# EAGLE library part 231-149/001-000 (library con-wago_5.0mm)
Serie 231, Stiftleiste mit geraden Einlötstiften / Series 231, Male connector with straight solder pins Polzahl / Pole No.: 19 Rastermaß / Pitch: 5 mm Bemessungsspannung / Rated Voltage: 320 V Nennstrom / Nominal Current: 12 A Lötstiftlänge: / Solder Pin Length: 5 mm Farbe / Color: grau / gray Stand: 01.01.2012. Die jeweils aktuellen Daten zu diesem Artikel finden Sie in unserem Produktkatalog, den Sie unter www.wago.com einsehen können. As of: 01/01/2012. Please find the newest data for this article in our product catalogue, which can be viewed under www.wago.com.

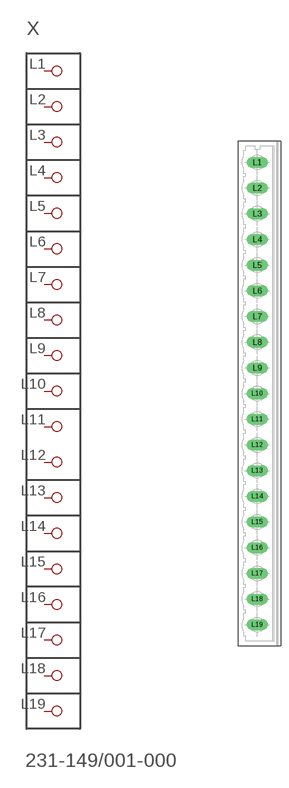
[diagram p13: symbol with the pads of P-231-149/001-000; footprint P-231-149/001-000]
Designator prefix X

## 231-149/001-000  [P-231-149/001-000]
L1  P1
L2  P2
L3  P3
L4  P4
L5  P5
L6  P6
L7  P7
L8  P8
L9  P9
L10  P10
L11  P11
L12  P12
L13  P13
L14  P14
L15  P15
L16  P16
L17  P17
L18  P18
L19  P19

## Footprint P-231-149/001-000 (pad centres in mm)
drill 1.4 long: L1 -0.4,45; L2 -0.4,40; L3 -0.4,35; L4 -0.4,30; L5 -0.4,25; L6 -0.4,20; L7 -0.4,15; L8 -0.4,10; L9 -0.4,5; L10 -0.4,0; L11 -0.4,-5; L12 -0.4,-10; L13 -0.4,-15; L14 -0.4,-20; L15 -0.4,-25; L16 -0.4,-30; L17 -0.4,-35; L18 -0.4,-40; L19 -0.4,-45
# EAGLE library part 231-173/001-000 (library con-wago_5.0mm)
Serie 231, Stiftleiste mit geraden Einlötstiften / Series 231, Male connector with straight solder pins Polzahl / Pole No.: 13 Rastermaß / Pitch: 5 mm Bemessungsspannung / Rated Voltage: 320 V Nennstrom / Nominal Current: 12 A Lötstiftlänge: / Solder Pin Length: 5 mm Farbe / Color: grau / gray Stand: 01.01.2012. Die jeweils aktuellen Daten zu diesem Artikel finden Sie in unserem Produktkatalog, den Sie unter www.wago.com einsehen können. As of: 01/01/2012. Please find the newest data for this article in our product catalogue, which can be viewed under www.wago.com.

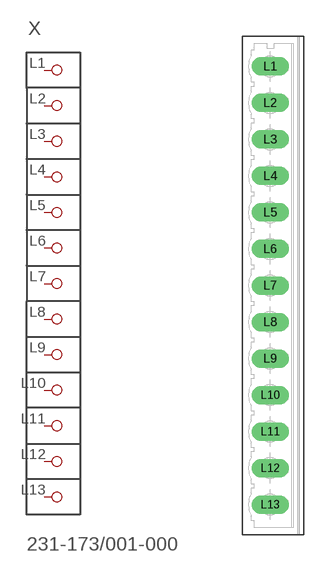
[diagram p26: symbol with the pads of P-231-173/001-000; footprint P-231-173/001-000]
Designator prefix X

## 231-173/001-000  [P-231-173/001-000]
L1  P1
L2  P2
L3  P3
L4  P4
L5  P5
L6  P6
L7  P7
L8  P8
L9  P9
L10  P10
L11  P11
L12  P12
L13  P13

## Footprint P-231-173/001-000 (pad centres in mm)
drill 1.7 long: L1 -0.4,30; L2 -0.4,25; L3 -0.4,20; L4 -0.4,15; L5 -0.4,10; L6 -0.4,5; L7 -0.4,0; L8 -0.4,-5; L9 -0.4,-10; L10 -0.4,-15; L11 -0.4,-20; L12 -0.4,-25; L13 -0.4,-30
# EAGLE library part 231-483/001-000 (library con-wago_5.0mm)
Serie 231, Stiftleiste mit abgewinkelten Einlötstiften / Series 231, Male connector with angled solder pins Polzahl / Pole No.: 23 Rastermaß / Pitch: 5 mm Bemessungsspannung / Rated Voltage: 320 V Nennstrom / Nominal Current: 16 A Lötstiftlänge: / Solder Pin Length: 3.8 mm Farbe / Color: grau / gray Stand: 01.01.2012. Die jeweils aktuellen Daten zu diesem Artikel finden Sie in unserem Produktkatalog, den Sie unter www.wago.com einsehen können. As of: 01/01/2012. Please find the newest data for this article in our product catalogue, which can be viewed under www.wago.com.

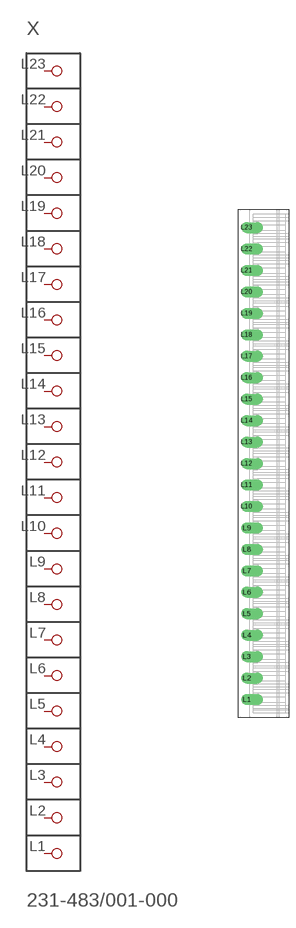
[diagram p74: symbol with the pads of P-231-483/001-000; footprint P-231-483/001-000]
Designator prefix X

## 231-483/001-000  [P-231-483/001-000]
L1  P1
L2  P2
L3  P3
L4  P4
L5  P5
L6  P6
L7  P7
L8  P8
L9  P9
L10  P10
L11  P11
L12  P12
L13  P13
L14  P14
L15  P15
L16  P16
L17  P17
L18  P18
L19  P19
L20  P20
L21  P21
L22  P22
L23  P23

## Footprint P-231-483/001-000 (pad centres in mm)
drill 1.7 offset: L1 -4,-55; L2 -4,-50; L3 -4,-45; L4 -4,-40; L5 -4,-35; L6 -4,-30; L7 -4,-25; L8 -4,-20; L9 -4,-15; L10 -4,-10; L11 -4,-5; L12 -4,0; L13 -4,5; L14 -4,10; L15 -4,15; L16 -4,20; L17 -4,25; L18 -4,30; L19 -4,35; L20 -4,40; L21 -4,45; L22 -4,50; L23 -4,55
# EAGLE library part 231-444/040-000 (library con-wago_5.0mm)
Serie 231, Stiftleiste (für Leiterplatten) Einlötstift abgewinkelt 1 x 1 mm / Series 231, Male header (for PCBs) Angled solder pin 1 x 1 mm Polzahl / Pole No.: 14 Rastermaß / Pitch: 5 mm Bemessungsspannung / Rated Voltage: 320 V Nennstrom / Nominal Current: 12 A Lötstiftlänge: / Solder Pin Length: 5 mm Farbe / Color: grau / gray Stand: 01.01.2012. Die jeweils aktuellen Daten zu diesem Artikel finden Sie in unserem Produktkatalog, den Sie unter www.wago.com einsehen können. As of: 01/01/2012. Please find the newest data for this article in our product catalogue, which can be viewed under www.wago.com.

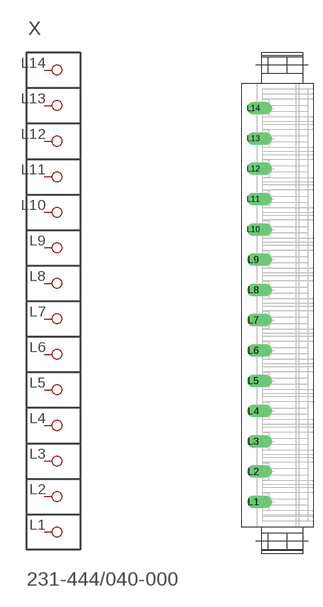
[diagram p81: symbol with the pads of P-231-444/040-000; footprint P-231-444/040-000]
Designator prefix X

## 231-444/040-000  [P-231-444/040-000]
L1  P1
L2  P2
L3  P3
L4  P4
L5  P5
L6  P6
L7  P7
L8  P8
L9  P9
L10  P10
L11  P11
L12  P12
L13  P13
L14  P14

## Footprint P-231-444/040-000 (pad centres in mm)
drill 1.4 offset: L1 -4,-32.8; L2 -4,-27.8; L3 -4,-22.8; L4 -4,-17.8; L5 -4,-12.8; L6 -4,-7.8; L7 -4,-2.8; L8 -4,2.2; L9 -4,7.2; L10 -4,12.2; L11 -4,17.2; L12 -4,22.2; L13 -4,27.2; L14 -4,32.2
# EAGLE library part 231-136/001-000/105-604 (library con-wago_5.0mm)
Serie 231, Stiftleiste mit geraden Einlötstiften / Series 231, Male connector with straight solder pins Polzahl / Pole No.: 6 Rastermaß / Pitch: 5 mm Bemessungsspannung / Rated Voltage: 320 V Nennstrom / Nominal Current: 12 A Lötstiftlänge: / Solder Pin Length: 2.4 mm Farbe / Color: schwarz / black Stand: 01.01.2012. Die jeweils aktuellen Daten zu diesem Artikel finden Sie in unserem Produktkatalog, den Sie unter www.wago.com einsehen können. As of: 01/01/2012. Please find the newest data for this article in our product catalogue, which can be viewed under www.wago.com.

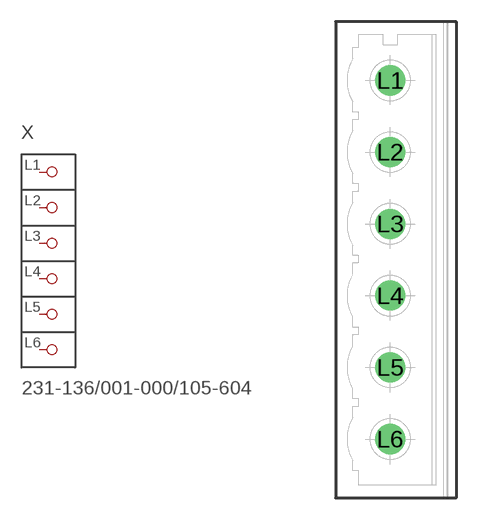
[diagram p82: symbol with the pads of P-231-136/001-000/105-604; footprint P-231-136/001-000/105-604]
Designator prefix X

## 231-136/001-000/105-604  [P-231-136/001-000/105-604]
L1  P1
L2  P2
L3  P3
L4  P4
L5  P5
L6  P6

## Footprint P-231-136/001-000/105-604 (pad centres in mm)
drill 1.4 round: L1 -0.4,12.5; L2 -0.4,7.5; L3 -0.4,2.5; L4 -0.4,-2.5; L5 -0.4,-7.5; L6 -0.4,-12.5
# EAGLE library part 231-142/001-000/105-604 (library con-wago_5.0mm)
Serie 231, Stiftleiste (für Leiterplatten) Einlötstift gerade 1 x 1 mm / Series 231, Male header (for PCBs) Straight solder pin 1 x 1 mm Polzahl / Pole No.: 12 Rastermaß / Pitch: 5 mm Bemessungsspannung / Rated Voltage: 320 V Nennstrom / Nominal Current: 12 A Lötstiftlänge: / Solder Pin Length: 2.4 mm Farbe / Color: schwarz / black Stand: 01.01.2012. Die jeweils aktuellen Daten zu diesem Artikel finden Sie in unserem Produktkatalog, den Sie unter www.wago.com einsehen können. As of: 01/01/2012. Please find the newest data for this article in our product catalogue, which can be viewed under www.wago.com.

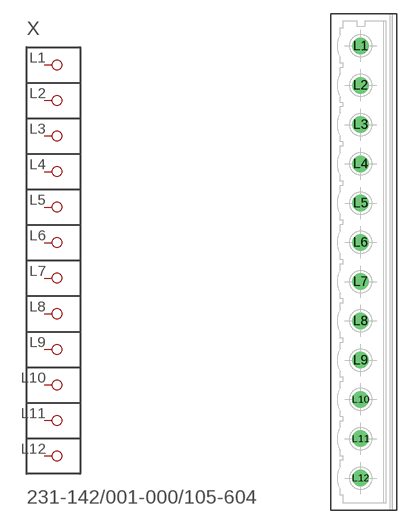
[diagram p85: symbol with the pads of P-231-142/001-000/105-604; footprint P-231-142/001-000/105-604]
Designator prefix X

## 231-142/001-000/105-604  [P-231-142/001-000/105-604]
L1  P1
L2  P2
L3  P3
L4  P4
L5  P5
L6  P6
L7  P7
L8  P8
L9  P9
L10  P10
L11  P11
L12  P12

## Footprint P-231-142/001-000/105-604 (pad centres in mm)
drill 1.4 round: L1 -0.4,27.5; L2 -0.4,22.5; L3 -0.4,17.5; L4 -0.4,12.5; L5 -0.4,7.5; L6 -0.4,2.5; L7 -0.4,-2.5; L8 -0.4,-7.5; L9 -0.4,-12.5; L10 -0.4,-17.5; L11 -0.4,-22.5; L12 -0.4,-27.5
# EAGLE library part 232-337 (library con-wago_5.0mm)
Serie 232, Aufstock-Stiftleisten Einlötstift abgewinkelt 1 x 1 mm / Series 232, Male headers for double-deck assembly Angled solder pin 1 x 1 mm Polzahl / Pole No.: 7 Rastermaß / Pitch: 5 mm Bemessungsspannung / Rated Voltage: 320 V Nennstrom / Nominal Current: 12 A Lötstiftlänge: / Solder Pin Length: 5 mm Farbe / Color: grau / gray Stand: 01.01.2012. Die jeweils aktuellen Daten zu diesem Artikel finden Sie in unserem Produktkatalog, den Sie unter www.wago.com einsehen können. As of: 01/01/2012. Please find the newest data for this article in our product catalogue, which can be viewed under www.wago.com.

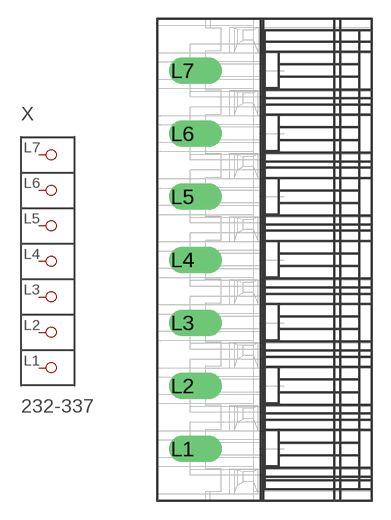
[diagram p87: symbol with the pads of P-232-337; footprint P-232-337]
Designator prefix X

## 232-337  [P-232-337]
L1  P1
L2  P2
L3  P3
L4  P4
L5  P5
L6  P6
L7  P7

## Footprint P-232-337 (pad centres in mm)
drill 1.4 offset: L1 -6.52,-15; L2 -6.52,-10; L3 -6.52,-5; L4 -6.52,0; L5 -6.52,5; L6 -6.52,10; L7 -6.52,15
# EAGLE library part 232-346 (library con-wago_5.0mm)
Serie 232, Aufstock-Stiftleisten mit abgewinkelten Einlötstiften / Series 232, Male headers for double-deck assembly with angled solder pins Polzahl / Pole No.: 16 Rastermaß / Pitch: 5 mm Bemessungsspannung / Rated Voltage: 320 V Nennstrom / Nominal Current: 12 A Lötstiftlänge: / Solder Pin Length: 5 mm Farbe / Color: grau / gray Stand: 01.01.2012. Die jeweils aktuellen Daten zu diesem Artikel finden Sie in unserem Produktkatalog, den Sie unter www.wago.com einsehen können. As of: 01/01/2012. Please find the newest data for this article in our product catalogue, which can be viewed under www.wago.com.

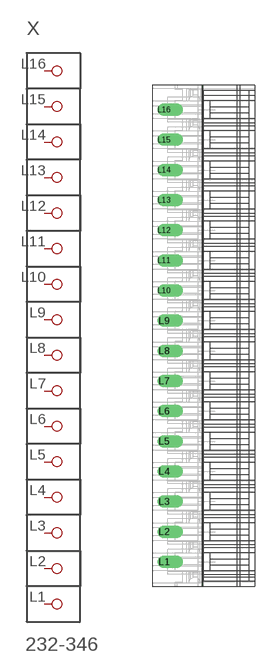
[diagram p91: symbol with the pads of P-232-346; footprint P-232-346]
Designator prefix X

## 232-346  [P-232-346]
L1  P1
L2  P2
L3  P3
L4  P4
L5  P5
L6  P6
L7  P7
L8  P8
L9  P9
L10  P10
L11  P11
L12  P12
L13  P13
L14  P14
L15  P15
L16  P16

## Footprint P-232-346 (pad centres in mm)
drill 1.4 offset: L1 -6.52,-37.5; L2 -6.52,-32.5; L3 -6.52,-27.5; L4 -6.52,-22.5; L5 -6.52,-17.5; L6 -6.52,-12.5; L7 -6.52,-7.5; L8 -6.52,-2.5; L9 -6.52,2.5; L10 -6.52,7.5; L11 -6.52,12.5; L12 -6.52,17.5; L13 -6.52,22.5; L14 -6.52,27.5; L15 -6.52,32.5; L16 -6.52,37.5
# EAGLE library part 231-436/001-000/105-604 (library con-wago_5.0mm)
Serie 231, Stiftleiste (für Leiterplatten) Einlötstift abgewinkelt 1 x 1 mm / Series 231, Male header (for PCBs) Angled solder pin 1 x 1 mm Polzahl / Pole No.: 6 Rastermaß / Pitch: 5 mm Bemessungsspannung / Rated Voltage: 320 V Nennstrom / Nominal Current: 12 A Lötstiftlänge: / Solder Pin Length: 2.4 mm Farbe / Color: schwarz / black Stand: 01.01.2012. Die jeweils aktuellen Daten zu diesem Artikel finden Sie in unserem Produktkatalog, den Sie unter www.wago.com einsehen können. As of: 01/01/2012. Please find the newest data for this article in our product catalogue, which can be viewed under www.wago.com.

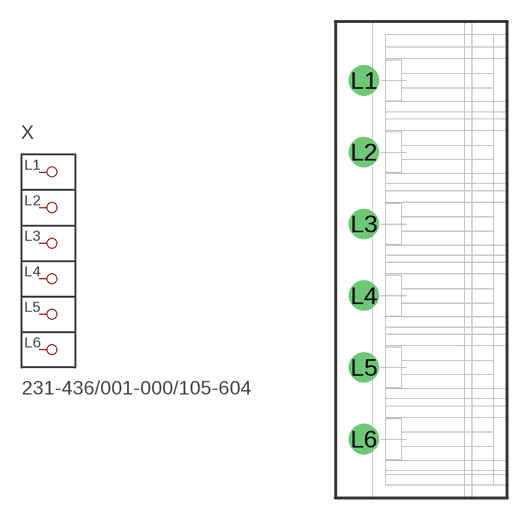
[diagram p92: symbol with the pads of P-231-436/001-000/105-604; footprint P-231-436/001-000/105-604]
Designator prefix X

## 231-436/001-000/105-604  [P-231-436/001-000/105-604]
L1  P1
L2  P2
L3  P3
L4  P4
L5  P5
L6  P6

## Footprint P-231-436/001-000/105-604 (pad centres in mm)
drill 1.4 round: L1 -4,12.5; L2 -4,7.5; L3 -4,2.5; L4 -4,-2.5; L5 -4,-7.5; L6 -4,-12.5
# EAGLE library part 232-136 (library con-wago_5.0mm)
Serie 232, Federleiste mit geraden Einlötstiften / Series 232, Female connector with straight solder pins Polzahl / Pole No.: 6 Rastermaß / Pitch: 5 mm Bemessungsspannung / Rated Voltage: 160 V Nennstrom / Nominal Current: 6 A Lötstiftlänge: / Solder Pin Length: 5 mm Farbe / Color: grau / gray Stand: 01.01.2012. Die jeweils aktuellen Daten zu diesem Artikel finden Sie in unserem Produktkatalog, den Sie unter www.wago.com einsehen können. As of: 01/01/2012. Please find the newest data for this article in our product catalogue, which can be viewed under www.wago.com.

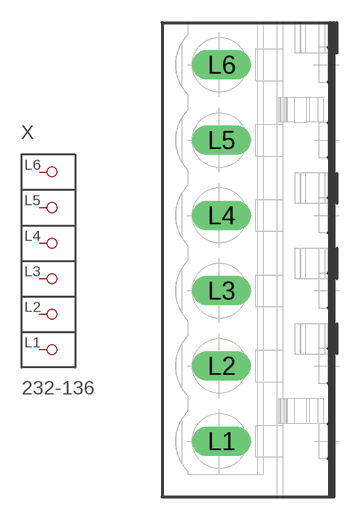
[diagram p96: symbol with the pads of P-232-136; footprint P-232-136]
Designator prefix X

## 232-136  [P-232-136]
L1  P1
L2  P2
L3  P3
L4  P4
L5  P5
L6  P6

## Footprint P-232-136 (pad centres in mm)
drill 1.3 long: L1 -1.923,-12.05; L2 -1.923,-7.05; L3 -1.923,-2.05; L4 -1.923,2.95; L5 -1.923,7.95; L6 -1.923,12.95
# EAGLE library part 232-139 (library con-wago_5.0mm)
Serie 232, Federleiste mit geraden Einlötstiften / Series 232, Female connector with straight solder pins Polzahl / Pole No.: 9 Rastermaß / Pitch: 5 mm Bemessungsspannung / Rated Voltage: 160 V Nennstrom / Nominal Current: 6 A Lötstiftlänge: / Solder Pin Length: 5 mm Farbe / Color: grau / gray Stand: 01.01.2012. Die jeweils aktuellen Daten zu diesem Artikel finden Sie in unserem Produktkatalog, den Sie unter www.wago.com einsehen können. As of: 01/01/2012. Please find the newest data for this article in our product catalogue, which can be viewed under www.wago.com.

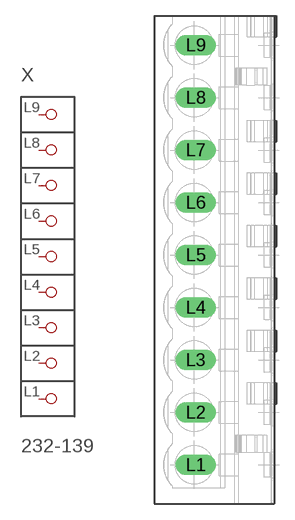
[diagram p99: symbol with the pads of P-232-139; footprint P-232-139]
Designator prefix X

## 232-139  [P-232-139]
L1  P1
L2  P2
L3  P3
L4  P4
L5  P5
L6  P6
L7  P7
L8  P8
L9  P9

## Footprint P-232-139 (pad centres in mm)
drill 1.3 long: L1 -1.995,-19.55; L2 -1.995,-14.55; L3 -1.995,-9.55; L4 -1.995,-4.55; L5 -1.995,0.45; L6 -1.995,5.45; L7 -1.995,10.45; L8 -1.995,15.45; L9 -1.995,20.45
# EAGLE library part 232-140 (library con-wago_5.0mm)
Serie 232, Federleiste mit geraden Einlötstiften / Series 232, Female connector with straight solder pins Polzahl / Pole No.: 10 Rastermaß / Pitch: 5 mm Bemessungsspannung / Rated Voltage: 160 V Nennstrom / Nominal Current: 6 A Lötstiftlänge: / Solder Pin Length: 5 mm Farbe / Color: grau / gray Stand: 01.01.2012. Die jeweils aktuellen Daten zu diesem Artikel finden Sie in unserem Produktkatalog, den Sie unter www.wago.com einsehen können. As of: 01/01/2012. Please find the newest data for this article in our product catalogue, which can be viewed under www.wago.com.

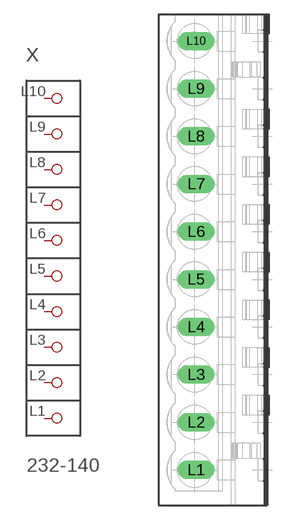
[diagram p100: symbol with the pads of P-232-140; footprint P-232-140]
Designator prefix X

## 232-140  [P-232-140]
L1  P1
L2  P2
L3  P3
L4  P4
L5  P5
L6  P6
L7  P7
L8  P8
L9  P9
L10  P10

## Footprint P-232-140 (pad centres in mm)
drill 1.3 long: L1 -2.019,-22.05; L2 -2.019,-17.05; L3 -2.019,-12.05; L4 -2.019,-7.05; L5 -2.019,-2.05; L6 -2.019,2.95; L7 -2.019,7.95; L8 -2.019,12.95; L9 -2.019,17.95; L10 -2.019,22.95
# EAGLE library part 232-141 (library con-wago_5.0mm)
Serie 232, Federleiste mit geraden Einlötstiften / Series 232, Female connector with straight solder pins Polzahl / Pole No.: 11 Rastermaß / Pitch: 5 mm Bemessungsspannung / Rated Voltage: 160 V Nennstrom / Nominal Current: 6 A Lötstiftlänge: / Solder Pin Length: 5 mm Farbe / Color: grau / gray Stand: 01.01.2012. Die jeweils aktuellen Daten zu diesem Artikel finden Sie in unserem Produktkatalog, den Sie unter www.wago.com einsehen können. As of: 01/01/2012. Please find the newest data for this article in our product catalogue, which can be viewed under www.wago.com.

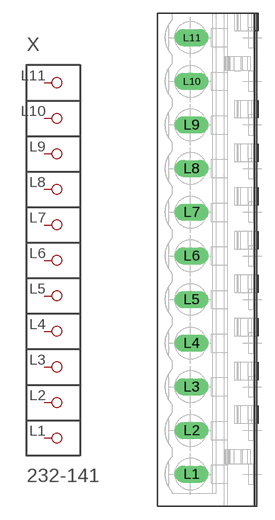
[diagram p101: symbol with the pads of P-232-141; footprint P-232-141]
Designator prefix X

## 232-141  [P-232-141]
L1  P1
L2  P2
L3  P3
L4  P4
L5  P5
L6  P6
L7  P7
L8  P8
L9  P9
L10  P10
L11  P11

## Footprint P-232-141 (pad centres in mm)
drill 1.3 long: L1 -2.043,-24.55; L2 -2.043,-19.55; L3 -2.043,-14.55; L4 -2.043,-9.55; L5 -2.043,-4.55; L6 -2.043,0.45; L7 -2.043,5.45; L8 -2.043,10.45; L9 -2.043,15.45; L10 -2.043,20.45; L11 -2.043,25.45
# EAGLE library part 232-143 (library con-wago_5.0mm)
Serie 232, Federleiste mit geraden Einlötstiften / Series 232, Female connector with straight solder pins Polzahl / Pole No.: 13 Rastermaß / Pitch: 5 mm Bemessungsspannung / Rated Voltage: 160 V Nennstrom / Nominal Current: 6 A Lötstiftlänge: / Solder Pin Length: 5 mm Farbe / Color: grau / gray Stand: 01.01.2012. Die jeweils aktuellen Daten zu diesem Artikel finden Sie in unserem Produktkatalog, den Sie unter www.wago.com einsehen können. As of: 01/01/2012. Please find the newest data for this article in our product catalogue, which can be viewed under www.wago.com.

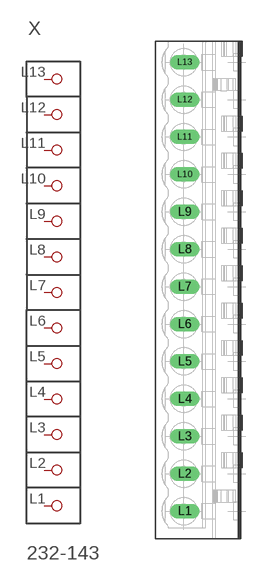
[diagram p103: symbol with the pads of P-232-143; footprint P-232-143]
Designator prefix X

## 232-143  [P-232-143]
L1  P1
L2  P2
L3  P3
L4  P4
L5  P5
L6  P6
L7  P7
L8  P8
L9  P9
L10  P10
L11  P11
L12  P12
L13  P13

## Footprint P-232-143 (pad centres in mm)
drill 1.3 long: L1 -2.092,-29.55; L2 -2.092,-24.55; L3 -2.092,-19.55; L4 -2.092,-14.55; L5 -2.092,-9.55; L6 -2.092,-4.55; L7 -2.092,0.45; L8 -2.092,5.45; L9 -2.092,10.45; L10 -2.092,15.45; L11 -2.092,20.45; L12 -2.092,25.45; L13 -2.092,30.45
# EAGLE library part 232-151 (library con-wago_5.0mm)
Serie 232, Federleiste mit geraden Einlötstiften / Series 232, Female connector with straight solder pins Polzahl / Pole No.: 21 Rastermaß / Pitch: 5 mm Bemessungsspannung / Rated Voltage: 160 V Nennstrom / Nominal Current: 6 A Lötstiftlänge: / Solder Pin Length: 5 mm Farbe / Color: grau / gray Stand: 01.01.2012. Die jeweils aktuellen Daten zu diesem Artikel finden Sie in unserem Produktkatalog, den Sie unter www.wago.com einsehen können. As of: 01/01/2012. Please find the newest data for this article in our product catalogue, which can be viewed under www.wago.com.

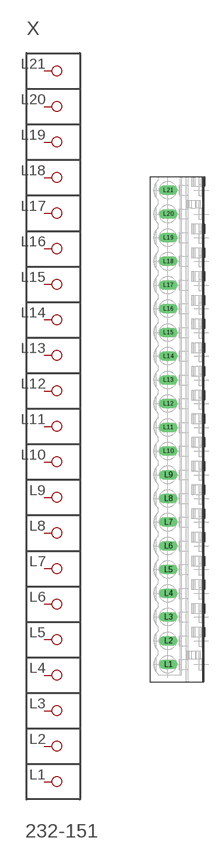
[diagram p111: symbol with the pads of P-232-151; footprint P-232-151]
Designator prefix X

## 232-151  [P-232-151]
L1  P1
L2  P2
L3  P3
L4  P4
L5  P5
L6  P6
L7  P7
L8  P8
L9  P9
L10  P10
L11  P11
L12  P12
L13  P13
L14  P14
L15  P15
L16  P16
L17  P17
L18  P18
L19  P19
L20  P20
L21  P21

## Footprint P-232-151 (pad centres in mm)
drill 1.3 long: L1 -2.29,-49.59; L2 -2.29,-44.59; L3 -2.29,-39.59; L4 -2.29,-34.59; L5 -2.29,-29.59; L6 -2.29,-24.59; L7 -2.29,-19.59; L8 -2.29,-14.59; L9 -2.29,-9.59; L10 -2.29,-4.59; L11 -2.29,0.41; L12 -2.29,5.41; L13 -2.29,10.41; L14 -2.29,15.41; L15 -2.29,20.41; L16 -2.29,25.41; L17 -2.29,30.41; L18 -2.29,35.41; L19 -2.29,40.41; L20 -2.29,45.41; L21 -2.29,50.41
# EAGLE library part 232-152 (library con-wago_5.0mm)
Serie 232, Federleiste mit geraden Einlötstiften / Series 232, Female connector with straight solder pins Polzahl / Pole No.: 22 Rastermaß / Pitch: 5 mm Bemessungsspannung / Rated Voltage: 160 V Nennstrom / Nominal Current: 6 A Lötstiftlänge: / Solder Pin Length: 5 mm Farbe / Color: grau / gray Stand: 01.01.2012. Die jeweils aktuellen Daten zu diesem Artikel finden Sie in unserem Produktkatalog, den Sie unter www.wago.com einsehen können. As of: 01/01/2012. Please find the newest data for this article in our product catalogue, which can be viewed under www.wago.com.

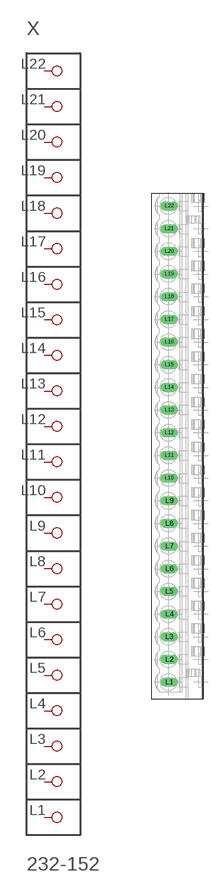
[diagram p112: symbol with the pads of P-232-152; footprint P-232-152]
Designator prefix X

## 232-152  [P-232-152]
L1  P1
L2  P2
L3  P3
L4  P4
L5  P5
L6  P6
L7  P7
L8  P8
L9  P9
L10  P10
L11  P11
L12  P12
L13  P13
L14  P14
L15  P15
L16  P16
L17  P17
L18  P18
L19  P19
L20  P20
L21  P21
L22  P22

## Footprint P-232-152 (pad centres in mm)
drill 1.3 long: L1 -2.315,-52.115; L2 -2.315,-47.115; L3 -2.315,-42.115; L4 -2.315,-37.115; L5 -2.315,-32.115; L6 -2.315,-27.115; L7 -2.315,-22.115; L8 -2.315,-17.115; L9 -2.315,-12.115; L10 -2.315,-7.115; L11 -2.315,-2.115; L12 -2.315,2.885; L13 -2.315,7.885; L14 -2.315,12.885; L15 -2.315,17.885; L16 -2.315,22.885; L17 -2.315,27.885; L18 -2.315,32.885; L19 -2.315,37.885; L20 -2.315,42.885; L21 -2.315,47.885; L22 -2.315,52.885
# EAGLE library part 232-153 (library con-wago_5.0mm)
Serie 232, Federleiste mit geraden Einlötstiften / Series 232, Female connector with straight solder pins Polzahl / Pole No.: 23 Rastermaß / Pitch: 5 mm Bemessungsspannung / Rated Voltage: 160 V Nennstrom / Nominal Current: 6 A Lötstiftlänge: / Solder Pin Length: 5 mm Farbe / Color: grau / gray Stand: 01.01.2012. Die jeweils aktuellen Daten zu diesem Artikel finden Sie in unserem Produktkatalog, den Sie unter www.wago.com einsehen können. As of: 01/01/2012. Please find the newest data for this article in our product catalogue, which can be viewed under www.wago.com.

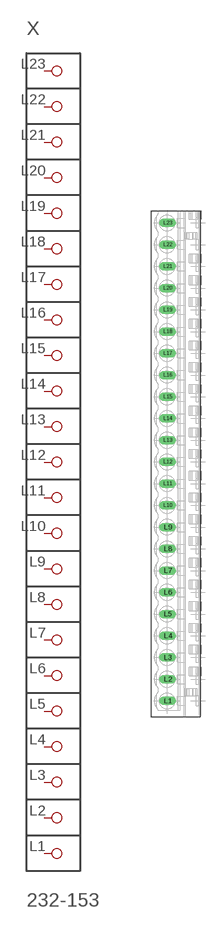
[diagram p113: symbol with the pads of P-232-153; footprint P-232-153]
Designator prefix X

## 232-153  [P-232-153]
L1  P1
L2  P2
L3  P3
L4  P4
L5  P5
L6  P6
L7  P7
L8  P8
L9  P9
L10  P10
L11  P11
L12  P12
L13  P13
L14  P14
L15  P15
L16  P16
L17  P17
L18  P18
L19  P19
L20  P20
L21  P21
L22  P22
L23  P23

## Footprint P-232-153 (pad centres in mm)
drill 1.3 long: L1 -2.34,-54.64; L2 -2.34,-49.64; L3 -2.34,-44.64; L4 -2.34,-39.64; L5 -2.34,-34.64; L6 -2.34,-29.64; L7 -2.34,-24.64; L8 -2.34,-19.64; L9 -2.34,-14.64; L10 -2.34,-9.64; L11 -2.34,-4.64; L12 -2.34,0.36; L13 -2.34,5.36; L14 -2.34,10.36; L15 -2.34,15.36; L16 -2.34,20.36; L17 -2.34,25.36; L18 -2.34,30.36; L19 -2.34,35.36; L20 -2.34,40.36; L21 -2.34,45.36; L22 -2.34,50.36; L23 -2.34,55.36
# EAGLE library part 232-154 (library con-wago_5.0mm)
Serie 232, Federleiste mit geraden Einlötstiften / Series 232, Female connector with straight solder pins Polzahl / Pole No.: 24 Rastermaß / Pitch: 5 mm Bemessungsspannung / Rated Voltage: 160 V Nennstrom / Nominal Current: 6 A Lötstiftlänge: / Solder Pin Length: 5 mm Farbe / Color: grau / gray Stand: 01.01.2012. Die jeweils aktuellen Daten zu diesem Artikel finden Sie in unserem Produktkatalog, den Sie unter www.wago.com einsehen können. As of: 01/01/2012. Please find the newest data for this article in our product catalogue, which can be viewed under www.wago.com.

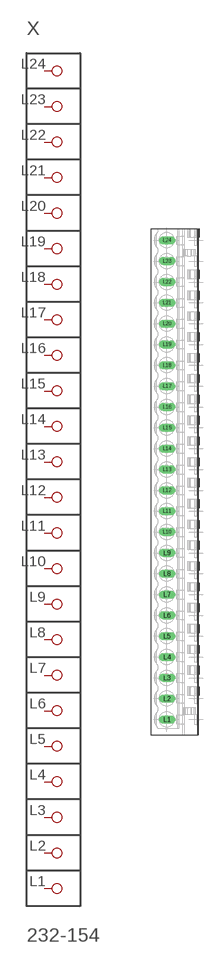
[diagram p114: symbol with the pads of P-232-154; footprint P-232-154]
Designator prefix X

## 232-154  [P-232-154]
L1  P1
L2  P2
L3  P3
L4  P4
L5  P5
L6  P6
L7  P7
L8  P8
L9  P9
L10  P10
L11  P11
L12  P12
L13  P13
L14  P14
L15  P15
L16  P16
L17  P17
L18  P18
L19  P19
L20  P20
L21  P21
L22  P22
L23  P23
L24  P24

## Footprint P-232-154 (pad centres in mm)
drill 1.3 long: L1 -2.365,-57.165; L2 -2.365,-52.165; L3 -2.365,-47.165; L4 -2.365,-42.165; L5 -2.365,-37.165; L6 -2.365,-32.165; L7 -2.365,-27.165; L8 -2.365,-22.165; L9 -2.365,-17.165; L10 -2.365,-12.165; L11 -2.365,-7.165; L12 -2.365,-2.165; L13 -2.365,2.835; L14 -2.365,7.835; L15 -2.365,12.835; L16 -2.365,17.835; L17 -2.365,22.835; L18 -2.365,27.835; L19 -2.365,32.835; L20 -2.365,37.835; L21 -2.365,42.835; L22 -2.365,47.835; L23 -2.365,52.835; L24 -2.365,57.835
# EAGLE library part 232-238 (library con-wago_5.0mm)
Serie 232, Federleiste mit abgewinkelten Einlötstiften / Series 232, Female connector with angled solder pins Polzahl / Pole No.: 8 Rastermaß / Pitch: 5 mm Bemessungsspannung / Rated Voltage: 160 V Nennstrom / Nominal Current: 6 A Lötstiftlänge: / Solder Pin Length: 5 mm Farbe / Color: grau / gray Stand: 01.01.2012. Die jeweils aktuellen Daten zu diesem Artikel finden Sie in unserem Produktkatalog, den Sie unter www.wago.com einsehen können. As of: 01/01/2012. Please find the newest data for this article in our product catalogue, which can be viewed under www.wago.com.

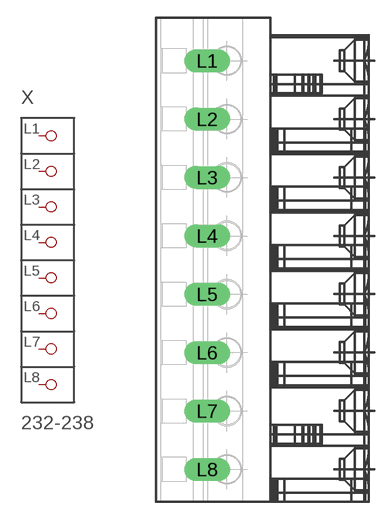
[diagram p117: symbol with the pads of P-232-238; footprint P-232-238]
Designator prefix X

## 232-238  [P-232-238]
L1  P1
L2  P2
L3  P3
L4  P4
L5  P5
L6  P6
L7  P7
L8  P8

## Footprint P-232-238 (pad centres in mm)
drill 1.3 long: L1 -4.961,17.05; L2 -4.961,12.05; L3 -4.961,7.05; L4 -4.961,2.05; L5 -4.961,-2.95; L6 -4.961,-7.95; L7 -4.961,-12.95; L8 -4.961,-17.95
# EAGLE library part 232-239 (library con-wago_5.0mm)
Serie 232, Federleiste mit abgewinkelten Einlötstiften / Series 232, Female connector with angled solder pins Polzahl / Pole No.: 9 Rastermaß / Pitch: 5 mm Bemessungsspannung / Rated Voltage: 160 V Nennstrom / Nominal Current: 6 A Lötstiftlänge: / Solder Pin Length: 5 mm Farbe / Color: grau / gray Stand: 01.01.2012. Die jeweils aktuellen Daten zu diesem Artikel finden Sie in unserem Produktkatalog, den Sie unter www.wago.com einsehen können. As of: 01/01/2012. Please find the newest data for this article in our product catalogue, which can be viewed under www.wago.com.

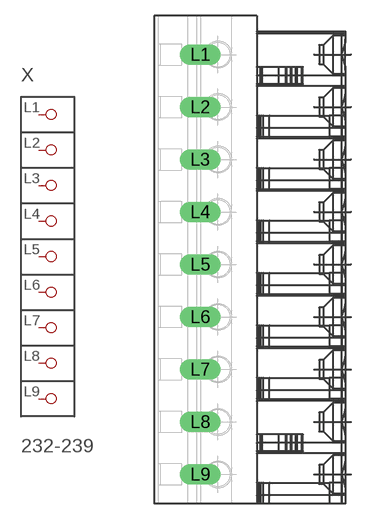
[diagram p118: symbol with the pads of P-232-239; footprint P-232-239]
Designator prefix X

## 232-239  [P-232-239]
L1  P1
L2  P2
L3  P3
L4  P4
L5  P5
L6  P6
L7  P7
L8  P8
L9  P9

## Footprint P-232-239 (pad centres in mm)
drill 1.3 long: L1 -4.984,19.55; L2 -4.984,14.55; L3 -4.984,9.55; L4 -4.984,4.55; L5 -4.984,-0.45; L6 -4.984,-5.45; L7 -4.984,-10.45; L8 -4.984,-15.45; L9 -4.984,-20.45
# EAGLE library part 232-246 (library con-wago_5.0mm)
Serie 232, Federleiste mit abgewinkelten Einlötstiften / Series 232, Female connector with angled solder pins Polzahl / Pole No.: 16 Rastermaß / Pitch: 5 mm Bemessungsspannung / Rated Voltage: 160 V Nennstrom / Nominal Current: 6 A Lötstiftlänge: / Solder Pin Length: 5 mm Farbe / Color: grau / gray Stand: 01.01.2012. Die jeweils aktuellen Daten zu diesem Artikel finden Sie in unserem Produktkatalog, den Sie unter www.wago.com einsehen können. As of: 01/01/2012. Please find the newest data for this article in our product catalogue, which can be viewed under www.wago.com.

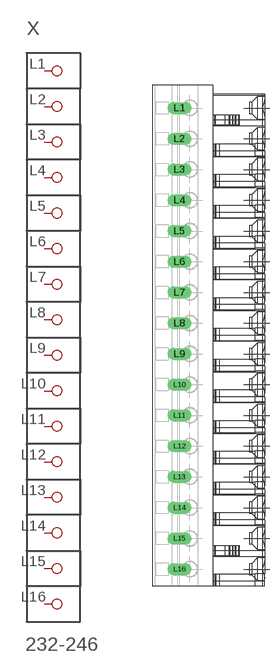
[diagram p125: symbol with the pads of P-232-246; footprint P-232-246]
Designator prefix X

## 232-246  [P-232-246]
L1  P1
L2  P2
L3  P3
L4  P4
L5  P5
L6  P6
L7  P7
L8  P8
L9  P9
L10  P10
L11  P11
L12  P12
L13  P13
L14  P14
L15  P15
L16  P16

## Footprint P-232-246 (pad centres in mm)
drill 1.3 long: L1 -5.15,37.05; L2 -5.15,32.05; L3 -5.15,27.05; L4 -5.15,22.05; L5 -5.15,17.05; L6 -5.15,12.05; L7 -5.15,7.05; L8 -5.15,2.05; L9 -5.15,-2.95; L10 -5.15,-7.95; L11 -5.15,-12.95; L12 -5.15,-17.95; L13 -5.15,-22.95; L14 -5.15,-27.95; L15 -5.15,-32.95; L16 -5.15,-37.95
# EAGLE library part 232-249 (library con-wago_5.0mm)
Serie 232, Federleiste mit abgewinkelten Einlötstiften / Series 232, Female connector with angled solder pins Polzahl / Pole No.: 19 Rastermaß / Pitch: 5 mm Bemessungsspannung / Rated Voltage: 160 V Nennstrom / Nominal Current: 6 A Lötstiftlänge: / Solder Pin Length: 5 mm Farbe / Color: grau / gray Stand: 01.01.2012. Die jeweils aktuellen Daten zu diesem Artikel finden Sie in unserem Produktkatalog, den Sie unter www.wago.com einsehen können. As of: 01/01/2012. Please find the newest data for this article in our product catalogue, which can be viewed under www.wago.com.

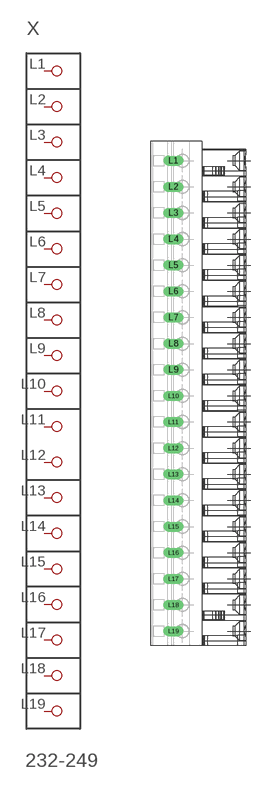
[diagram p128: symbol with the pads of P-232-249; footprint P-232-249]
Designator prefix X

## 232-249  [P-232-249]
L1  P1
L2  P2
L3  P3
L4  P4
L5  P5
L6  P6
L7  P7
L8  P8
L9  P9
L10  P10
L11  P11
L12  P12
L13  P13
L14  P14
L15  P15
L16  P16
L17  P17
L18  P18
L19  P19

## Footprint P-232-249 (pad centres in mm)
drill 1.3 long: L1 -5.223,44.55; L2 -5.223,39.55; L3 -5.223,34.55; L4 -5.223,29.55; L5 -5.223,24.55; L6 -5.223,19.55; L7 -5.223,14.55; L8 -5.223,9.55; L9 -5.223,4.55; L10 -5.223,-0.45; L11 -5.223,-5.45; L12 -5.223,-10.45; L13 -5.223,-15.45; L14 -5.223,-20.45; L15 -5.223,-25.45; L16 -5.223,-30.45; L17 -5.223,-35.45; L18 -5.223,-40.45; L19 -5.223,-45.45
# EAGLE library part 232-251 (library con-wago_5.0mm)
Serie 232, Federleiste mit abgewinkelten Einlötstiften / Series 232, Female connector with angled solder pins Polzahl / Pole No.: 21 Rastermaß / Pitch: 5 mm Bemessungsspannung / Rated Voltage: 160 V Nennstrom / Nominal Current: 6 A Lötstiftlänge: / Solder Pin Length: 5 mm Farbe / Color: grau / gray Stand: 01.01.2012. Die jeweils aktuellen Daten zu diesem Artikel finden Sie in unserem Produktkatalog, den Sie unter www.wago.com einsehen können. As of: 01/01/2012. Please find the newest data for this article in our product catalogue, which can be viewed under www.wago.com.

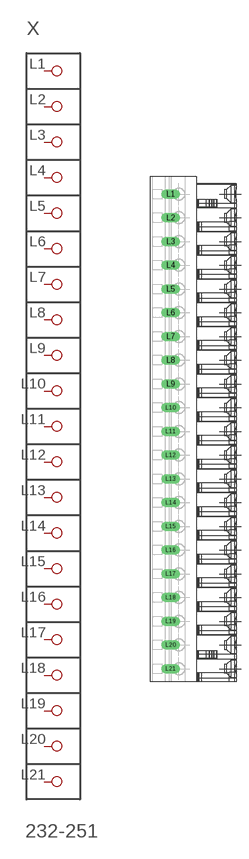
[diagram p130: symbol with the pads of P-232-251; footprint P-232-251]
Designator prefix X

## 232-251  [P-232-251]
L1  P1
L2  P2
L3  P3
L4  P4
L5  P5
L6  P6
L7  P7
L8  P8
L9  P9
L10  P10
L11  P11
L12  P12
L13  P13
L14  P14
L15  P15
L16  P16
L17  P17
L18  P18
L19  P19
L20  P20
L21  P21

## Footprint P-232-251 (pad centres in mm)
drill 1.3 long: L1 -5.272,49.55; L2 -5.272,44.55; L3 -5.272,39.55; L4 -5.272,34.55; L5 -5.272,29.55; L6 -5.272,24.55; L7 -5.272,19.55; L8 -5.272,14.55; L9 -5.272,9.55; L10 -5.272,4.55; L11 -5.272,-0.45; L12 -5.272,-5.45; L13 -5.272,-10.45; L14 -5.272,-15.45; L15 -5.272,-20.45; L16 -5.272,-25.45; L17 -5.272,-30.45; L18 -5.272,-35.45; L19 -5.272,-40.45; L20 -5.272,-45.45; L21 -5.272,-50.45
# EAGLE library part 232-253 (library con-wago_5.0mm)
Serie 232, Federleiste mit abgewinkelten Einlötstiften / Series 232, Female connector with angled solder pins Polzahl / Pole No.: 23 Rastermaß / Pitch: 5 mm Bemessungsspannung / Rated Voltage: 160 V Nennstrom / Nominal Current: 6 A Lötstiftlänge: / Solder Pin Length: 5 mm Farbe / Color: grau / gray Stand: 01.01.2012. Die jeweils aktuellen Daten zu diesem Artikel finden Sie in unserem Produktkatalog, den Sie unter www.wago.com einsehen können. As of: 01/01/2012. Please find the newest data for this article in our product catalogue, which can be viewed under www.wago.com.

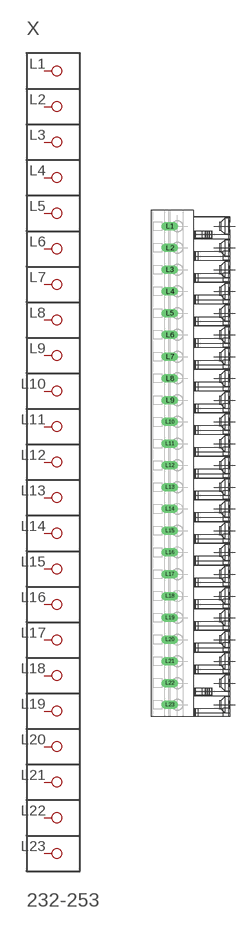
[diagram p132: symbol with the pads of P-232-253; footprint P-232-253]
Designator prefix X

## 232-253  [P-232-253]
L1  P1
L2  P2
L3  P3
L4  P4
L5  P5
L6  P6
L7  P7
L8  P8
L9  P9
L10  P10
L11  P11
L12  P12
L13  P13
L14  P14
L15  P15
L16  P16
L17  P17
L18  P18
L19  P19
L20  P20
L21  P21
L22  P22
L23  P23

## Footprint P-232-253 (pad centres in mm)
drill 1.3 long: L1 -5.321,54.55; L2 -5.321,49.55; L3 -5.321,44.55; L4 -5.321,39.55; L5 -5.321,34.55; L6 -5.321,29.55; L7 -5.321,24.55; L8 -5.321,19.55; L9 -5.321,14.55; L10 -5.321,9.55; L11 -5.321,4.55; L12 -5.321,-0.45; L13 -5.321,-5.45; L14 -5.321,-10.45; L15 -5.321,-15.45; L16 -5.321,-20.45; L17 -5.321,-25.45; L18 -5.321,-30.45; L19 -5.321,-35.45; L20 -5.321,-40.45; L21 -5.321,-45.45; L22 -5.321,-50.45; L23 -5.321,-55.45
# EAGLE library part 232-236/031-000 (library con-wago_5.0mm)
Serie 232, Federleiste mit abgewinkelten Einlötstiften / Series 232, Female connector with angled solder pins Polzahl / Pole No.: 6 Rastermaß / Pitch: 5 mm Bemessungsspannung / Rated Voltage: 160 V Nennstrom / Nominal Current: 6 A Lötstiftlänge: / Solder Pin Length: 5 mm Farbe / Color: grau / gray Stand: 01.01.2012. Die jeweils aktuellen Daten zu diesem Artikel finden Sie in unserem Produktkatalog, den Sie unter www.wago.com einsehen können. As of: 01/01/2012. Please find the newest data for this article in our product catalogue, which can be viewed under www.wago.com.

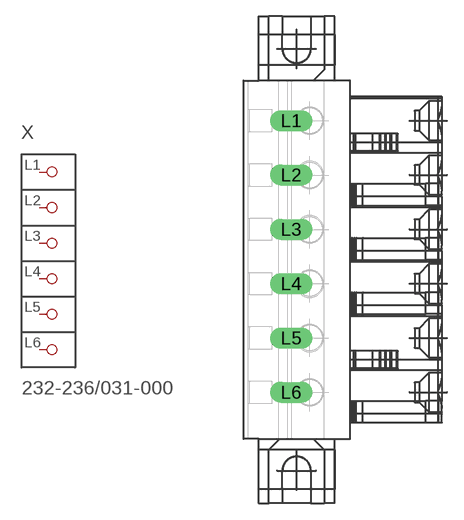
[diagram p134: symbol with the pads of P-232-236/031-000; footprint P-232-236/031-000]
Designator prefix X

## 232-236/031-000  [P-232-236/031-000]
L1  P1
L2  P2
L3  P3
L4  P4
L5  P5
L6  P6

## Footprint P-232-236/031-000 (pad centres in mm)
drill 1.3 long: L1 -4.973,12.8; L2 -4.973,7.8; L3 -4.973,2.8; L4 -4.973,-2.2; L5 -4.973,-7.2; L6 -4.973,-12.2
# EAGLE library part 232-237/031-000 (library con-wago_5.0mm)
Serie 232, Federleiste mit abgewinkelten Einlötstiften / Series 232, Female connector with angled solder pins Polzahl / Pole No.: 7 Rastermaß / Pitch: 5 mm Bemessungsspannung / Rated Voltage: 160 V Nennstrom / Nominal Current: 6 A Lötstiftlänge: / Solder Pin Length: 5 mm Farbe / Color: grau / gray Stand: 01.01.2012. Die jeweils aktuellen Daten zu diesem Artikel finden Sie in unserem Produktkatalog, den Sie unter www.wago.com einsehen können. As of: 01/01/2012. Please find the newest data for this article in our product catalogue, which can be viewed under www.wago.com.

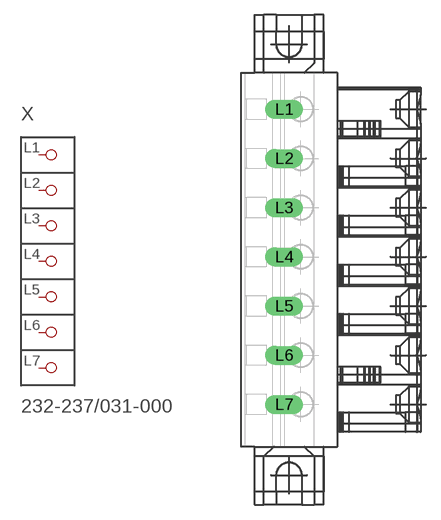
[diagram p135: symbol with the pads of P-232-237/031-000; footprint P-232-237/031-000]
Designator prefix X

## 232-237/031-000  [P-232-237/031-000]
L1  P1
L2  P2
L3  P3
L4  P4
L5  P5
L6  P6
L7  P7

## Footprint P-232-237/031-000 (pad centres in mm)
drill 1.3 long: L1 -4.995,15.3; L2 -4.995,10.3; L3 -4.995,5.3; L4 -4.995,0.3; L5 -4.995,-4.7; L6 -4.995,-9.7; L7 -4.995,-14.7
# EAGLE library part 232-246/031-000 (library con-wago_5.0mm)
Serie 232, Federleiste mit abgewinkelten Einlötstiften / Series 232, Female connector with angled solder pins Polzahl / Pole No.: 16 Rastermaß / Pitch: 5 mm Bemessungsspannung / Rated Voltage: 160 V Nennstrom / Nominal Current: 6 A Lötstiftlänge: / Solder Pin Length: 5 mm Farbe / Color: grau / gray Stand: 01.01.2012. Die jeweils aktuellen Daten zu diesem Artikel finden Sie in unserem Produktkatalog, den Sie unter www.wago.com einsehen können. As of: 01/01/2012. Please find the newest data for this article in our product catalogue, which can be viewed under www.wago.com.

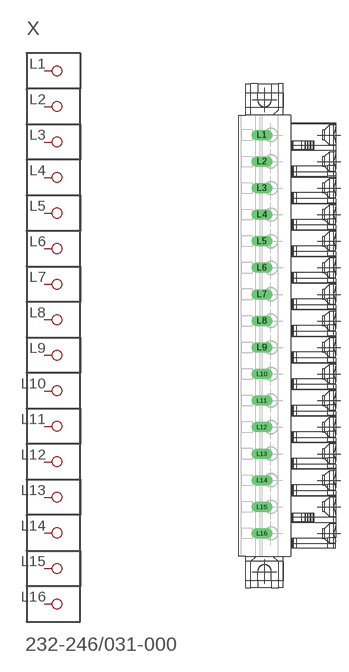
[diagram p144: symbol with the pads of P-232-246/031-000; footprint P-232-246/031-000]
Designator prefix X

## 232-246/031-000  [P-232-246/031-000]
L1  P1
L2  P2
L3  P3
L4  P4
L5  P5
L6  P6
L7  P7
L8  P8
L9  P9
L10  P10
L11  P11
L12  P12
L13  P13
L14  P14
L15  P15
L16  P16

## Footprint P-232-246/031-000 (pad centres in mm)
drill 1.3 long: L1 -5.211,37.8; L2 -5.211,32.8; L3 -5.211,27.8; L4 -5.211,22.8; L5 -5.211,17.8; L6 -5.211,12.8; L7 -5.211,7.8; L8 -5.211,2.8; L9 -5.211,-2.2; L10 -5.211,-7.2; L11 -5.211,-12.2; L12 -5.211,-17.2; L13 -5.211,-22.2; L14 -5.211,-27.2; L15 -5.211,-32.2; L16 -5.211,-37.2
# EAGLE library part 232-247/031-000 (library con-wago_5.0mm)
Serie 232, Federleiste mit abgewinkelten Einlötstiften / Series 232, Female connector with angled solder pins Polzahl / Pole No.: 17 Rastermaß / Pitch: 5 mm Bemessungsspannung / Rated Voltage: 160 V Nennstrom / Nominal Current: 6 A Lötstiftlänge: / Solder Pin Length: 5 mm Farbe / Color: grau / gray Stand: 01.01.2012. Die jeweils aktuellen Daten zu diesem Artikel finden Sie in unserem Produktkatalog, den Sie unter www.wago.com einsehen können. As of: 01/01/2012. Please find the newest data for this article in our product catalogue, which can be viewed under www.wago.com.

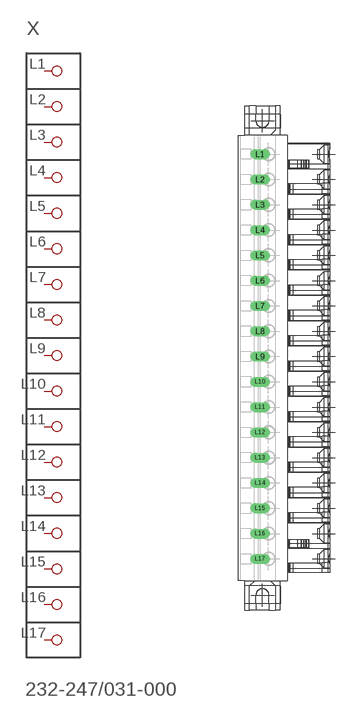
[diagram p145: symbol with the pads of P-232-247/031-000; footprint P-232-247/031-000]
Designator prefix X

## 232-247/031-000  [P-232-247/031-000]
L1  P1
L2  P2
L3  P3
L4  P4
L5  P5
L6  P6
L7  P7
L8  P8
L9  P9
L10  P10
L11  P11
L12  P12
L13  P13
L14  P14
L15  P15
L16  P16
L17  P17

## Footprint P-232-247/031-000 (pad centres in mm)
drill 1.3 long: L1 -5.235,40.3; L2 -5.235,35.3; L3 -5.235,30.3; L4 -5.235,25.3; L5 -5.235,20.3; L6 -5.235,15.3; L7 -5.235,10.3; L8 -5.235,5.3; L9 -5.235,0.3; L10 -5.235,-4.7; L11 -5.235,-9.7; L12 -5.235,-14.7; L13 -5.235,-19.7; L14 -5.235,-24.7; L15 -5.235,-29.7; L16 -5.235,-34.7; L17 -5.235,-39.7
